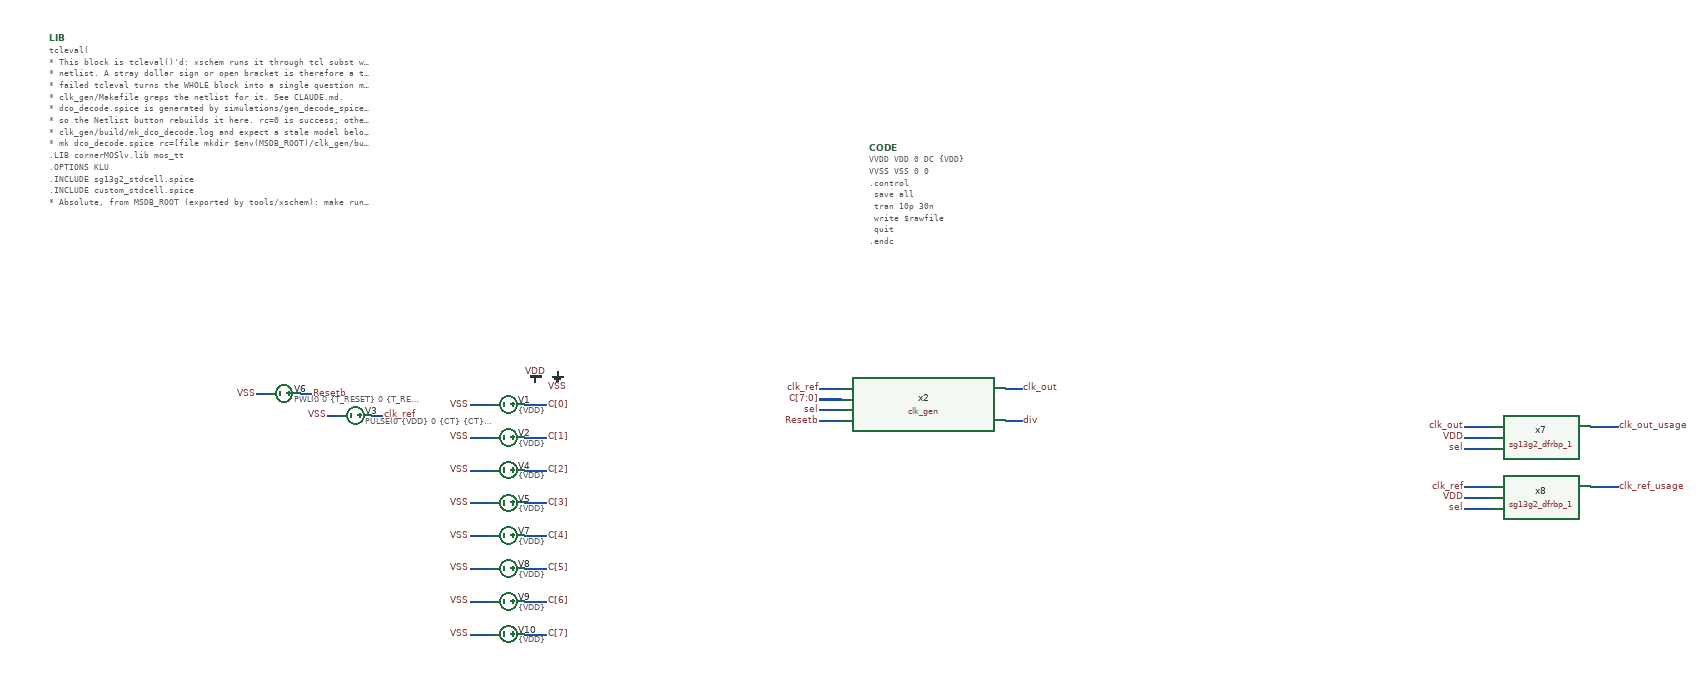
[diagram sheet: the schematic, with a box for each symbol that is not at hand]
v {xschem version=3.4.7 file_version=1.2}
G {}
K {}
V {}
S {}
E {}
B 2 150 -490 950 -90 {flags=graph
y1=-1.6309838
y2=4.3409845
ypos1=0.88341962
ypos2=2.4194035
divy=5
subdivy=1
unity=1
x1=2.0708532e-08
x2=3.271773e-08
divx=5
subdivx=1
xlabmag=1.0
ylabmag=1.0
node="\\"clk_r;clk_ref 3 +\\"
\\"cru; clk_ref_usage 1.5 +\\"
\\"clk_o;clk_out 3 +\\"
\\"cou; clk_out_usage 1.5 +\\"
sel
div
div_rstb; x2.div_rstb 1.5 -
m_out; x2.m_out 1.5 -
m_outb; x2.m_outb 1.5 -
clk4; x2.clk4 1.5 -
clk2; x2.clk2 1.5 -"
color="4 5 6 7 8 9 10 11 12 13 14"
dataset=-1
unitx=1
logx=0
logy=0
digital=0}
N -1000 100 -980 100 {lab=clk_ref}
N -1080 100 -1060 100 {lab=VSS}
N -1130 60 -1110 60 {lab=Resetb}
N -1210 60 -1190 60 {lab=VSS}
N -820 80 -780 80 {lab=VSS}
N -720 80 -680 80 {lab=C[0]}
N -720 140 -680 140 {lab=C[1]}
N -720 260 -680 260 {lab=C[3]}
N -720 200 -680 200 {lab=C[2]}
N -820 140 -780 140 {lab=VSS}
N -820 200 -780 200 {lab=VSS}
N -820 260 -780 260 {lab=VSS}
N -720 320 -680 320 {lab=C[4]}
N -820 320 -780 320 {lab=VSS}
N 1000 120 1050 120 {lab=clk_out}
N 1000 140 1050 140 {lab=VDD}
N 1000 160 1050 160 {lab=sel}
N 1000 230 1050 230 {lab=clk_ref}
N 1000 250 1050 250 {lab=VDD}
N 1000 270 1050 270 {lab=sel}
N 1230 120 1280 120 {lab=clk_out_usage}
N 1230 230 1280 230 {lab=clk_ref_usage}
N -720 380 -680 380 {lab=C[5]}
N -820 380 -780 380 {lab=VSS}
N -720 440 -680 440 {lab=C[6]}
N -820 440 -780 440 {lab=VSS}
N -720 500 -680 500 {lab=C[7]}
N -820 500 -780 500 {lab=VSS}
N -180 50 -140 50 {lab=clk_ref}
N -180 70 -140 70 {lab=C[7:0] bus=true}
N -180 90 -140 90 {lab=sel}
N -180 110 -140 110 {lab=Resetb}
N 160 50 190 50 {lab=clk_out}
N 160 110 190 110 {lab=div}
C {lab_pin.sym} -680 140 2 0 {name=p1 sig_type=std_logic lab=C[1]}
C {gnd.sym} -660 20 0 0 {name=l1 lab=VSS}
C {vdd.sym} -700 40 0 0 {name=l2 lab=VDD}
C {lab_pin.sym} -680 80 2 0 {name=p4 sig_type=std_logic lab=C[0]}
C {vsource.sym} -1030 100 1 0 {name=V3 value="PULSE(0 \{VDD\} 0 \{CT\} \{CT\} \{T_REF/2\} \{T_REF\}" savecurrent=false}
C {lab_pin.sym} -980 100 2 0 {name=p6 sig_type=std_logic lab=clk_ref}
C {lab_pin.sym} -1080 100 0 0 {name=p7 sig_type=std_logic lab=VSS}
C {lab_pin.sym} -680 260 2 0 {name=p8 sig_type=std_logic lab=C[3]}
C {lab_pin.sym} -680 200 2 0 {name=p10 sig_type=std_logic lab=C[2]}
C {vsource.sym} -1160 60 1 0 {name=V6 value="PWL(0 0 \{T_RESET\} 0 \{T_RESET + CT\} \{VDD\})" savecurrent=false}
C {lab_pin.sym} -1110 60 2 0 {name=p12 sig_type=std_logic lab=Resetb
value="PWL(0 \{VDD\} \{T_FREQ + CT\}"}
C {lab_pin.sym} -1210 60 0 0 {name=p13 sig_type=std_logic lab=VSS
value="PWL(0 \{VDD\} \{T_FREQ + CT\}"}
C {code_shown.sym} -1590 -590 0 0 {name=LIB only_toplevel=false value="tcleval(
* This block is tcleval()'d: xschem runs it through tcl subst when writing the
* netlist. A stray dollar sign or open bracket is therefore a tcl error, and a
* failed tcleval turns the WHOLE block into a single question mark, silently.
* clk_gen/Makefile greps the netlist for it. See CLAUDE.md.

* dco_decode.spice is generated by simulations/gen_decode_spice.py, not drawn,
* so the Netlist button rebuilds it here. rc=0 is success; otherwise read
* clk_gen/build/mk_dco_decode.log and expect a stale model below.
* mk dco_decode.spice rc=[file mkdir $env(MSDB_ROOT)/clk_gen/build][catch \{exec make -s -C $env(MSDB_ROOT)/clk_gen simulations/dco_decode.spice >& $env(MSDB_ROOT)/clk_gen/build/mk_dco_decode.log\}]

.LIB cornerMOSlv.lib mos_tt
.OPTIONS KLU
.INCLUDE sg13g2_stdcell.spice
.INCLUDE custom_stdcell.spice

* Absolute, from MSDB_ROOT (exported by tools/xschem): make runs ngspice from
* clk_gen/, the Simulate button from netlist_dir (the repo root), so a relative
* include only works for one of them.
.INCLUDE $env(MSDB_ROOT)/clk_gen/simulations/dco_decode.spice

* Same for the raw file, handed to the CODE block as an ngspice variable.
* setcs, not set: set lower-cases its value.
.control
  setcs rawfile = $env(MSDB_ROOT)/clk_gen/simulations/test_clk_gen.raw
.endc
.PARAM VDD=1.2
.PARAM T_REF=10n
.PARAM CT=50p
.PARAM TEMP=28
.PARAM T_RESET=\{T_REF + 0.1n\}
)"
place=header}
C {code_shown.sym} -90 -390 0 0 {name=CODE only_toplevel=false value="
VVDD VDD 0 DC \{VDD\}
VVSS VSS 0 0
.control
  save all
  tran 10p 30n
  write $rawfile
  quit
.endc
"}
C {vsource.sym} -750 80 1 0 {name=V1 value=\{VDD\} savecurrent=false}
C {lab_pin.sym} -820 80 0 0 {name=p3 sig_type=std_logic lab=VSS}
C {vsource.sym} -750 140 1 0 {name=V2 value=\{VDD\} savecurrent=false}
C {lab_pin.sym} -820 140 0 0 {name=p5 sig_type=std_logic lab=VSS}
C {vsource.sym} -750 200 1 0 {name=V4 value=\{VDD\} savecurrent=false}
C {lab_pin.sym} -820 200 0 0 {name=p9 sig_type=std_logic lab=VSS}
C {vsource.sym} -750 260 1 0 {name=V5 value=\{VDD\} savecurrent=false}
C {lab_pin.sym} -820 260 0 0 {name=p11 sig_type=std_logic lab=VSS}
C {lab_pin.sym} -680 320 2 0 {name=p21 sig_type=std_logic lab=C[4]}
C {vsource.sym} -750 320 1 0 {name=V7 value=\{VDD\} savecurrent=false}
C {lab_pin.sym} -820 320 0 0 {name=p22 sig_type=std_logic lab=VSS}
C {sg13g2_dfrbp_1.sym} 1140 140 0 0 {name=x7 VDD=VDD VSS=VSS prefix=sg13g2_ }
C {lab_pin.sym} 1000 120 2 1 {name=p20 sig_type=std_logic lab=clk_out}
C {lab_pin.sym} 1000 140 2 1 {name=p23 sig_type=std_logic lab=VDD}
C {lab_pin.sym} 1000 160 0 0 {name=p24 sig_type=std_logic lab=sel}
C {sg13g2_dfrbp_1.sym} 1140 250 0 0 {name=x8 VDD=VDD VSS=VSS prefix=sg13g2_ }
C {lab_pin.sym} 1000 230 2 1 {name=p25 sig_type=std_logic lab=clk_ref}
C {lab_pin.sym} 1000 250 2 1 {name=p26 sig_type=std_logic lab=VDD}
C {lab_pin.sym} 1000 270 0 0 {name=p27 sig_type=std_logic lab=sel}
C {lab_pin.sym} 1280 120 2 0 {name=p28 sig_type=std_logic lab=clk_out_usage}
C {lab_pin.sym} 1280 230 2 0 {name=p32 sig_type=std_logic lab=clk_ref_usage}
C {lab_pin.sym} -680 380 2 0 {name=p33 sig_type=std_logic lab=C[5]}
C {vsource.sym} -750 380 1 0 {name=V8 value=\{VDD\} savecurrent=false
lab=C[5]}
C {lab_pin.sym} -820 380 0 0 {name=p31 sig_type=std_logic lab=VSS}
C {lab_pin.sym} -680 440 2 0 {name=p34 sig_type=std_logic lab=C[6]}
C {vsource.sym} -750 440 1 0 {name=V9 value=\{VDD\} savecurrent=false
lab=C[5]}
C {lab_pin.sym} -820 440 0 0 {name=p35 sig_type=std_logic lab=VSS}
C {lab_pin.sym} -680 500 2 0 {name=p36 sig_type=std_logic lab=C[7]}
C {vsource.sym} -750 500 1 0 {name=V10 value=\{VDD\} savecurrent=false
lab=C[5]}
C {lab_pin.sym} -820 500 0 0 {name=p37 sig_type=std_logic lab=VSS}
C {clk_gen/clk_gen.sym} 10 80 0 0 {name=x2}
C {lab_pin.sym} -180 50 0 0 {name=p38 sig_type=std_logic lab=clk_ref}
C {lab_pin.sym} -180 70 0 0 {name=p39 sig_type=std_logic lab=C[7:0]}
C {lab_pin.sym} -180 90 0 0 {name=p40 sig_type=std_logic lab=sel}
C {lab_pin.sym} -180 110 0 0 {name=p41 sig_type=std_logic lab=Resetb}
C {lab_pin.sym} 190 50 2 0 {name=p42 sig_type=std_logic lab=clk_out}
C {lab_pin.sym} 190 110 2 0 {name=p2 sig_type=std_logic lab=div
}
